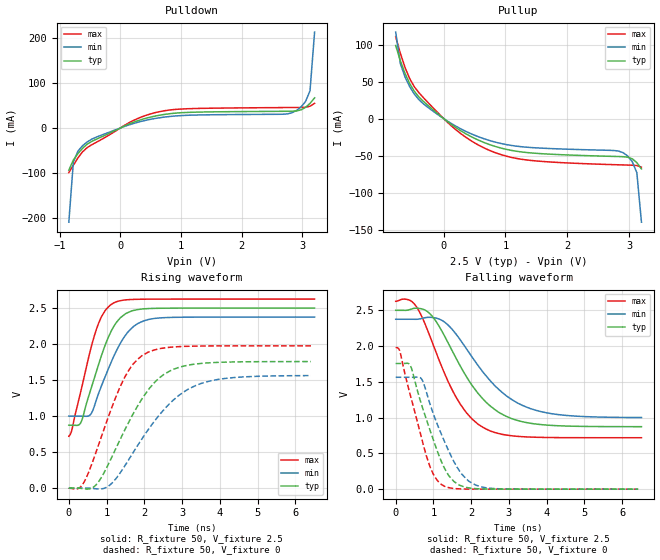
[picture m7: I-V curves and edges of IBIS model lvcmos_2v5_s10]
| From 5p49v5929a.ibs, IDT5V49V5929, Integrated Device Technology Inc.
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[Model]   lvcmos_2v5_s10
Model_type   Output
Polarity   Non-Inverting
|   typ   min   max
C_comp   2pF   1.5pF   2.5pF
Vmeas = 1.25V
Rref = 50
Cref = 0
Vref = 1.25V
|   typ   min   max
[Voltage range]   2.5V   2.375V   2.625V
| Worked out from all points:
|   slope of the pulldown table from 0 to 0.375 V, typ, clamps not added: 18.9 ohm
|   slope of the pullup table from 0 to 0.375 V, typ, clamps not added: 17.6 ohm
|   rising waveform, R_fixture 50, V_fixture 2.5: 20-80 % time 636ps typ, 708ps min, 552ps max; typ from 0.873 V to 2.5 V
|   falling waveform, R_fixture 50, V_fixture 2.5: 20-80 % time 1.17ns typ, 1.32ns min, 1ns max; typ from 2.5 V to 0.873 V
|   rising waveform, R_fixture 50, V_fixture 0: 20-80 % time 1.1ns typ, 1.34ns min, 874ps max; typ from 0 V to 1.76 V
|   falling waveform, R_fixture 50, V_fixture 0: 20-80 % time 679ps typ, 746ps min, 598ps max; typ from 1.76 V to 0 V
[Pulldown]
|Voltage   I (typ)   I (min)   I (max)
|Note, modeling breaks down at 250mA and above.  This is well beyond the functional   |
|operating range of the device.  Should this scenario occur, catastrophic failure and   |
|possible damage to the device and/or board is of higher concern than the I-V curve   |
|behavior.  The IBIS checker will flag currents in excess of 10A with warnings.  Lines   |
|with currents in excess of 0.35 A have been commented out.  The points still remain|
|available to the user if the user desires to use them.   |
|-2.50000e+00   -2.65608e+02   -2.29941e+02   -3.26165e+02
|-2.42500e+00   -2.52343e+02   -2.18875e+02   -3.09252e+02
|-2.35000e+00   -2.39080e+02   -2.07811e+02   -2.92340e+02
|-2.27500e+00   -2.25818e+02   -1.96747e+02   -2.75428e+02
|-2.20000e+00   -2.12557e+02   -1.85685e+02   -2.58518e+02
|-2.12500e+00   -1.99297e+02   -1.74624e+02   -2.41608e+02
|-2.05000e+00   -1.86039e+02   -1.63565e+02   -2.24700e+02
|-1.97500e+00   -1.72782e+02   -1.52508e+02   -2.07793e+02
|-1.90000e+00   -1.59528e+02   -1.41453e+02   -1.90888e+02
|-1.82500e+00   -1.46276e+02   -1.30401e+02   -1.73985e+02
|-1.75000e+00   -1.33027e+02   -1.19352e+02   -1.57085e+02
|-1.67500e+00   -1.19782e+02   -1.08307e+02   -1.40188e+02
|-1.60000e+00   -1.06542e+02   -9.72682e+01   -1.23295e+02
|-1.52500e+00   -9.33090e+01   -8.62359e+01   -1.06409e+02
|-1.45000e+00   -8.00850e+01   -7.52129e+01   -8.95309e+01
|-1.37500e+00   -6.68743e+01   -6.42029e+01   -7.26657e+01
|-1.30000e+00   -5.36897e+01   -5.32178e+01   -5.58258e+01
|-1.22500e+00   -4.05463e+01   -4.22664e+01   -3.90371e+01
|-1.15000e+00   -2.74527e+01   -3.13543e+01   -2.23159e+01
|-1.07500e+00   -1.44175e+01   -2.04874e+01   -5.67477e+00
|-1.00000e+00   -2.41445e+00   -9.65733e+00   -2.99544e-01
|-9.25000e-01   -2.45532e-01   -1.42571e+00   -1.20411e-01
-850mV    -93.99mA   -210mA     -99.45mA
-775mV    -71.55mA   -76.14mA   -83.12mA
-700mV    -57.23mA   -51.66mA   -66.79mA
-550mV    -36.49mA   -31.4mA    -44.03mA
200mV     11.86mA    9.308mA    15.7mA
650mV     28.48mA    22.79mA    36.43mA
1.175V    34.92mA    28.53mA    43.11mA
2.825V    37.25mA    33.68mA    45.54mA
2.975V    40.25mA    46.76mA    45.71mA
3.05V     45.87mA    58.57mA    46.09mA
3.125V    54.76mA    82.96mA    48.46mA
3.2V      67.01mA    213.6mA    54.81mA
| 3.27500e+00   8.22893e-02   1.48202e+00   6.52461e-02
| 3.35000e+00   1.11691e-01   1.21021e+01   7.95740e-02
| 3.42500e+00   4.17187e-01   2.91692e+01   9.49987e-02
| 3.50000e+00   5.44922e+00   4.62676e+01   1.08609e-01
| 3.57500e+00   2.52763e+01   6.34104e+01   1.52479e-01
| 3.65000e+00   4.58138e+01   8.05959e+01   1.32846e+00
| 3.72500e+00   6.64097e+01   9.78129e+01   2.01980e+01
| 3.80000e+00   8.70553e+01   1.15052e+02   4.64595e+01
| 3.87500e+00   1.07734e+02   1.32307e+02   7.28003e+01
| 3.95000e+00   1.28434e+02   1.49572e+02   9.91974e+01
| 4.02500e+00   1.49148e+02   1.66846e+02   1.25626e+02
| 4.10000e+00   1.69871e+02   1.84125e+02   1.52073e+02
| 4.17500e+00   1.90602e+02   2.01410e+02   1.78532e+02
| 4.25000e+00   2.11338e+02   2.18698e+02   2.05000e+02
| 4.32500e+00   2.32079e+02   2.35990e+02   2.31473e+02
| 4.40000e+00   2.52823e+02   2.53284e+02   2.57951e+02
| 4.47500e+00   2.73570e+02   2.70581e+02   2.84433e+02
| 4.55000e+00   2.94320e+02   2.87880e+02   3.10918e+02
| 4.62500e+00   3.15072e+02   3.05181e+02   3.37405e+02
| 4.70000e+00   3.35826e+02   3.22484e+02   3.63895e+02
| 4.77500e+00   3.56582e+02   3.39789e+02   3.90387e+02
| 4.85000e+00   3.77340e+02   3.57095e+02   4.16881e+02
| 4.92500e+00   3.98099e+02   3.74402e+02   4.43377e+02
| 5.00000e+00   4.18860e+02   3.91711e+02   4.69874e+02
[Pullup]
|Voltage   I (typ)   I (min)   I (max)
|Note, modeling breaks down at 250mA and above.  This is well beyond the functional   |
|operating range of the device.  Should this scenario occur, catastrophic failure and   |
|possible damage to the device and/or board is of higher concern than the I-V curve   |
|behavior.  The IBIS checker will flag currents in excess of 10A with warnings.  Lines   |
|with currents in excess of 0.35 A have been commented out.  The points still remain|
|available to the user if the user desires to use them.   |
|-2.50000e+00   4.18924e+02   3.62922e+02   5.14110e+02
|-2.42500e+00   3.98163e+02   3.45615e+02   4.87611e+02
|-2.35000e+00   3.77403e+02   3.28309e+02   4.61112e+02
|-2.27500e+00   3.56644e+02   3.11005e+02   4.34615e+02
|-2.20000e+00   3.35887e+02   2.93702e+02   4.08119e+02
|-2.12500e+00   3.15132e+02   2.76401e+02   3.81625e+02
|-2.05000e+00   2.94379e+02   2.59102e+02   3.55132e+02
|-1.97500e+00   2.73627e+02   2.41805e+02   3.28642e+02
|-1.90000e+00   2.52879e+02   2.24511e+02   3.02154e+02
|-1.82500e+00   2.32133e+02   2.07220e+02   2.75668e+02
|-1.75000e+00   2.11391e+02   1.89933e+02   2.49186e+02
|-1.67500e+00   1.90653e+02   1.72650e+02   2.22708e+02
|-1.60000e+00   1.69920e+02   1.55373e+02   1.96234e+02
|-1.52500e+00   1.49194e+02   1.38102e+02   1.69767e+02
|-1.45000e+00   1.28478e+02   1.20842e+02   1.43309e+02
|-1.37500e+00   1.07776e+02   1.03595e+02   1.16864e+02
|-1.30000e+00   8.70950e+01   8.63670e+01   9.04416e+01
|-1.22500e+00   6.64470e+01   6.91675e+01   6.40570e+01
|-1.15000e+00   4.58485e+01   5.20071e+01   3.77381e+01
|-1.07500e+00   2.53080e+01   3.48921e+01   1.14975e+01
|-1.00000e+00   5.47770e+00   1.78138e+01   5.20511e-01
|-9.25000e-01   4.42241e-01   3.17254e+00   1.56153e-01
|-8.50000e-01   1.32908e-01   3.92497e-01   1.29698e-01
-775mV    98.68mA    116.8mA    110.3mA
-700mV    78.11mA    74.31mA    88.11mA
-625mV    61.11mA    56.31mA    69.18mA
-475mV    36.93mA    33.22mA    43.05mA
-325mV    23.07mA    19.8mA     28.08mA
125mV     -7.951mA   -6.687mA   -9.848mA
575mV     -29.56mA   -24.95mA   -36.3mA
1.325V    -45.7mA    -38.54mA   -55.7mA
2.9V      -51.46mA   -45.91mA   -62.61mA
3.05V     -54.28mA   -57.96mA   -62.98mA
3.125V    -59.49mA   -72.96mA   -63.43mA
3.2V      -67.99mA   -139.9mA   -65.6mA
| 3.27500e+00   -7.95179e-02   -7.11252e-01   -7.19088e-02
| 3.35000e+00   -9.96915e-02   -6.05603e+00   -8.27613e-02
| 3.42500e+00   -2.49209e-01   -1.68766e+01   -9.65190e-02
| 3.50000e+00   -2.41654e+00   -2.77285e+01   -1.10622e-01
| 3.57500e+00   -1.44189e+01   -3.86247e+01   -1.40364e-01
| 3.65000e+00   -2.74535e+01   -4.95634e+01   -6.78328e-01
| 3.72500e+00   -4.05466e+01   -6.05360e+01   -1.12141e+01
| 3.80000e+00   -5.36896e+01   -7.15395e+01   -2.78806e+01
| 3.87500e+00   -6.68736e+01   -8.25581e+01   -4.46279e+01
| 3.95000e+00   -8.00835e+01   -9.35871e+01   -6.14343e+01
| 4.02500e+00   -9.33072e+01   -1.04624e+02   -7.82862e+01
| 4.10000e+00   -1.06540e+02   -1.15666e+02   -9.51560e+01
| 4.17500e+00   -1.19780e+02   -1.26714e+02   -1.12037e+02
| 4.25000e+00   -1.33024e+02   -1.37764e+02   -1.28926e+02
| 4.32500e+00   -1.46273e+02   -1.48818e+02   -1.45820e+02
| 4.40000e+00   -1.59525e+02   -1.59874e+02   -1.62718e+02
| 4.47500e+00   -1.72779e+02   -1.70933e+02   -1.79619e+02
| 4.55000e+00   -1.86036e+02   -1.81993e+02   -1.96523e+02
| 4.62500e+00   -1.99294e+02   -1.93055e+02   -2.13429e+02
| 4.70000e+00   -2.12554e+02   -2.04118e+02   -2.30337e+02
| 4.77500e+00   -2.25816e+02   -2.15182e+02   -2.47246e+02
| 4.85000e+00   -2.39078e+02   -2.26248e+02   -2.64156e+02
| 4.92500e+00   -2.52342e+02   -2.37314e+02   -2.81068e+02
| 5.00000e+00   -2.65606e+02   -2.48382e+02   -2.97980e+02
[Ramp]
|   typ   min   max
dV/dt_r   1.062/1.108n   0.945/1.348n   1.194/0.879n
dV/dt_f   0.993/1.179n   0.84/1.332n   1.162/1.013n
R_load =   50
[Rising Waveform]
R_fixture = 50
V_fixture = 2.5   |Vcc_typ
V_fixture_min = 2.375 |Vcc_min
V_fixture_max = 2.625 |Vcc_max
C_fixture = 0.0p
| Time   typ   min   max
| 0.00000e+00   8.73021e-01   9.99328e-01   7.18803e-01
| 2.82958e-12   8.73021e-01   9.99328e-01   7.18803e-01
| 5.01945e-12   8.73021e-01   9.99328e-01   7.18803e-01
| 5.29250e-12   8.73021e-01   9.99328e-01   7.18803e-01
| 8.83938e-12   8.73021e-01   9.99328e-01   7.18803e-01
| 1.58159e-11   8.73021e-01   9.99328e-01   7.18803e-01
| 1.65816e-11   8.73021e-01   9.99328e-01   7.18803e-01
| 3.09307e-11   8.73021e-01   9.99328e-01   7.18803e-01
| 4.33456e-11   8.73021e-01   9.99328e-01   7.18803e-01
| 4.84997e-11   8.73021e-01   9.99328e-01   7.18803e-01
| 5.92498e-11   8.73021e-01   9.99328e-01   7.18803e-01
| 6.33903e-11   8.73021e-01   9.99328e-01   7.18803e-01
| 7.24942e-11   8.73021e-01   9.99328e-01   7.18803e-01
| 7.37142e-11   8.73021e-01   9.99328e-01   7.18803e-01
| 7.72112e-11   8.73021e-01   9.99328e-01   7.18803e-01
| 8.08094e-11   8.73021e-01   9.99328e-01   7.18803e-01
| 8.33740e-11   8.73021e-01   9.99328e-01   7.18803e-01
| 8.93880e-11   8.73021e-01   9.99328e-01   7.18803e-01
| 1.00166e-10   8.73021e-01   9.99328e-01   7.18804e-01
| 1.04900e-10   8.73021e-01   9.99328e-01   7.18804e-01
| 1.14234e-10   8.73022e-01   9.99329e-01   7.18804e-01
| 1.18465e-10   8.73022e-01   9.99329e-01   7.18804e-01
| 1.25023e-10   8.73022e-01   9.99329e-01   7.18804e-01
| 1.37358e-10   8.73022e-01   9.99329e-01   7.18804e-01
| 1.40589e-10   8.73022e-01   9.99329e-01   7.18804e-01
| 1.51767e-10   8.73021e-01   9.99329e-01   7.18802e-01
| 1.61060e-10   8.73019e-01   9.99327e-01   7.18800e-01
| 1.69091e-10   8.73016e-01   9.99324e-01   7.18797e-01
| 1.80923e-10   8.73011e-01   9.99320e-01   7.18792e-01
| 1.98540e-10   8.73004e-01   9.99312e-01   7.18784e-01
| 2.03752e-10   8.73002e-01   9.99309e-01   7.18782e-01
| 2.22970e-10   8.72994e-01   9.99302e-01   7.18775e-01
| 2.39229e-10   8.72989e-01   9.99297e-01   7.18772e-01
| 2.45359e-10   8.72988e-01   9.99296e-01   7.18773e-01
| 2.53236e-10   8.72988e-01   9.99294e-01   7.18776e-01
| 2.61834e-10   8.72990e-01   9.99294e-01   7.18782e-01
| 2.68845e-10   8.72993e-01   9.99294e-01   7.18785e-01
| 2.75098e-10   8.72996e-01   9.99296e-01   7.18788e-01
| 2.84408e-10   8.73000e-01   9.99300e-01   7.18791e-01
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0s        873mV      999.3mV    718.8mV
80.48ps   872.2mV    998.7mV    807.1mV
308.1ps   900.3mV    998.4mV    1.322V
585.2ps   1.376V     1.029V     1.942V
865.1ps   1.841V     1.42V      2.381V
1.196ns   2.249V     1.835V     2.574V
1.366ns   2.366V     2.012V     2.603V
1.631ns   2.452V     2.204V     2.618V
2.106ns   2.493V     2.341V     2.624V
6.509ns   2.5V       2.375V     2.625V
[Falling Waveform]
R_fixture = 50
V_fixture = 2.5   |Vcc_typ
V_fixture_min = 2.375 |Vcc_min
V_fixture_max = 2.625 |Vcc_max
C_fixture = 0.0p
| Time   typ   min   max
| 0.00000e+00   2.50000e+00   2.37500e+00   2.62500e+00
| 2.82958e-12   2.50000e+00   2.37500e+00   2.62500e+00
| 5.01945e-12   2.50000e+00   2.37500e+00   2.62500e+00
| 5.29250e-12   2.50000e+00   2.37500e+00   2.62500e+00
| 8.83938e-12   2.50000e+00   2.37500e+00   2.62500e+00
| 1.58159e-11   2.50000e+00   2.37500e+00   2.62500e+00
| 1.65816e-11   2.50000e+00   2.37500e+00   2.62500e+00
| 3.09306e-11   2.50000e+00   2.37500e+00   2.62500e+00
| 4.33456e-11   2.50000e+00   2.37500e+00   2.62500e+00
| 4.84997e-11   2.50000e+00   2.37500e+00   2.62500e+00
| 5.92499e-11   2.50000e+00   2.37500e+00   2.62500e+00
| 6.33904e-11   2.50000e+00   2.37500e+00   2.62500e+00
| 7.24942e-11   2.50000e+00   2.37500e+00   2.62500e+00
| 7.37143e-11   2.50000e+00   2.37500e+00   2.62500e+00
| 7.72112e-11   2.50000e+00   2.37500e+00   2.62500e+00
| 8.08094e-11   2.50000e+00   2.37500e+00   2.62500e+00
| 8.33740e-11   2.50000e+00   2.37500e+00   2.62500e+00
| 8.93881e-11   2.50000e+00   2.37500e+00   2.62500e+00
| 1.00162e-10   2.50000e+00   2.37500e+00   2.62500e+00
| 1.04901e-10   2.50000e+00   2.37500e+00   2.62500e+00
| 1.14235e-10   2.50000e+00   2.37500e+00   2.62500e+00
| 1.18460e-10   2.50000e+00   2.37500e+00   2.62500e+00
| 1.25023e-10   2.50000e+00   2.37500e+00   2.62500e+00
| 1.37358e-10   2.50000e+00   2.37500e+00   2.62500e+00
| 1.40585e-10   2.50000e+00   2.37500e+00   2.62500e+00
| 1.51766e-10   2.50000e+00   2.37500e+00   2.62500e+00
| 1.61057e-10   2.50000e+00   2.37500e+00   2.62500e+00
| 1.69080e-10   2.50000e+00   2.37500e+00   2.62500e+00
| 1.80919e-10   2.49999e+00   2.37500e+00   2.62499e+00
| 1.99499e-10   2.49999e+00   2.37499e+00   2.62499e+00
| 2.05003e-10   2.49999e+00   2.37499e+00   2.62499e+00
| 2.24273e-10   2.49998e+00   2.37498e+00   2.62498e+00
| 2.39981e-10   2.49998e+00   2.37498e+00   2.62498e+00
| 2.47899e-10   2.49998e+00   2.37498e+00   2.62498e+00
| 2.62665e-10   2.49998e+00   2.37498e+00   2.62499e+00
| 2.73527e-10   2.49998e+00   2.37498e+00   2.62499e+00
| 2.79768e-10   2.49998e+00   2.37498e+00   2.62499e+00
| 2.89155e-10   2.49999e+00   2.37498e+00   2.62500e+00
| 2.95491e-10   2.49999e+00   2.37498e+00   2.62500e+00
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0s        2.5V       2.375V     2.625V
478.7ps   2.527V     2.375V     2.597V
923ps     2.444V     2.401V     2.115V
1.275ns   2.159V     2.343V     1.642V
1.606ns   1.824V     2.163V     1.28V
1.998ns   1.47V      1.865V     994.9mV
2.318ns   1.257V     1.632V     861.7mV
2.924ns   1.019V     1.307V     756.9mV
3.686ns   911.9mV    1.107V     726mV
6.509ns   873.4mV    1.001V     718.8mV
[Rising Waveform]
R_fixture = 50
V_fixture = 0
C_fixture = 0.0p
| Time   typ   min   max
| 0.00000e+00   6.87937e-09   4.94005e-08   5.62352e-09
| 2.82958e-12   9.38656e-09   5.18161e-08   8.19508e-09
| 5.01945e-12   1.05516e-08   5.29861e-08   9.33315e-09
| 5.29250e-12   1.06562e-08   5.30562e-08   9.47156e-09
| 8.83938e-12   1.14741e-08   5.38988e-08   1.01694e-08
| 1.58159e-11   9.80859e-09   5.35126e-08   7.82907e-09
| 1.65816e-11   9.85399e-09   5.39566e-08   7.55918e-09
| 3.09307e-11   1.50805e-08   6.38774e-08   9.11730e-09
| 4.33456e-11   5.21227e-08   9.86830e-08   4.07091e-08
| 4.84997e-11   6.75010e-08   1.14222e-07   5.79266e-08
| 5.92498e-11   1.01050e-07   1.49539e-07   9.24295e-08
| 6.33903e-11   1.01613e-07   1.48222e-07   1.03899e-07
| 7.24942e-11   7.31413e-08   1.02772e-07   9.86080e-08
| 7.37142e-11   5.87738e-08   7.73613e-08   9.03171e-08
| 7.72112e-11   -3.94951e-09   4.52995e-09   5.74755e-08
| 8.08094e-11   -7.54237e-08   -9.71747e-08   1.81975e-08
| 8.33740e-11   -1.30062e-07   -1.50154e-07   1.62220e-08
| 8.93880e-11   -1.48519e-07   -2.64374e-07   4.53045e-08
| 1.00166e-10   1.24254e-07   -4.29323e-08   3.33852e-07
| 1.04900e-10   3.01602e-07   1.48683e-07   5.72718e-07
| 1.14234e-10   9.37278e-07   7.74393e-07   9.81604e-07
| 1.18465e-10   1.16633e-06   1.08464e-06   1.13897e-06
| 1.25023e-10   1.50552e-06   1.56545e-06   1.16097e-06
| 1.37358e-10   1.64317e-06   1.93794e-06   9.99908e-07
| 1.40589e-10   1.48293e-06   1.94633e-06   9.03754e-07
| 1.51767e-10   5.03721e-07   1.34352e-06   -1.49195e-07
| 1.61060e-10   -1.03002e-06   -4.00874e-07   -2.42878e-06
| 1.69091e-10   -3.75459e-06   -2.59222e-06   -4.51622e-06
| 1.80923e-10   -7.88012e-06   -6.70546e-06   -9.20462e-06
| 1.98540e-10   -1.48331e-05   -1.37393e-05   -1.59118e-05
| 2.03752e-10   -1.65288e-05   -1.57793e-05   -1.78548e-05
| 2.22970e-10   -2.24873e-05   -2.19399e-05   -2.34613e-05
| 2.39229e-10   -2.68323e-05   -2.61765e-05   -2.48219e-05
| 2.45359e-10   -2.73690e-05   -2.77433e-05   -2.41161e-05
| 2.53236e-10   -2.75121e-05   -2.88971e-05   -2.07569e-05
| 2.61834e-10   -2.50538e-05   -2.91232e-05   -1.51028e-05
| 2.68845e-10   -2.15946e-05   -2.81639e-05   -1.16643e-05
| 2.75098e-10   -1.87424e-05   -2.59563e-05   -8.96290e-06
| 2.84409e-10   -1.48308e-05   -2.25961e-05   -6.64248e-06
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0s        6.879nV    49.4nV     5.624nV
349.5ps   -5.964mV   81.91uV    38.42mV
744.3ps   58.17mV    -11.4mV    533.7mV
1.077ns   362.8mV    37.42mV    1.033V
1.444ns   765.9mV    276.5mV    1.5V
1.932ns   1.234V     679mV      1.837V
2.572ns   1.595V     1.12V      1.95V
3.498ns   1.731V     1.452V     1.973V
4.458ns   1.752V     1.538V     1.975V
6.413ns   1.757V     1.562V     1.975V
[Falling Waveform]
R_fixture = 50
V_fixture = 0
C_fixture = 0.0p
| Time   typ   min   max
| 0.00000e+00   1.75700e+00   1.56389e+00   1.97545e+00
| 1.87623e-10   1.75699e+00   1.56388e+00   1.97544e+00
| 2.18725e-10   1.75698e+00   1.56387e+00   1.97543e+00
| 2.63808e-10   1.75697e+00   1.56386e+00   1.97543e+00
| 3.01812e-10   1.75699e+00   1.56387e+00   1.97544e+00
| 3.86470e-10   1.75699e+00   1.56388e+00   1.97545e+00
| 4.31207e-10   1.75700e+00   1.56389e+00   1.97545e+00
| 7.14375e-10   1.75700e+00   1.56390e+00   1.97546e+00
| 7.53456e-10   1.75700e+00   1.56389e+00   1.97545e+00
| 8.44629e-10   1.75700e+00   1.56390e+00   1.97544e+00
| 9.20641e-10   1.75699e+00   1.56390e+00   1.97545e+00
| 9.89803e-10   1.75699e+00   1.56389e+00   1.97546e+00
| 1.05820e-09   1.75699e+00   1.56389e+00   1.97546e+00
| 1.12623e-09   1.75701e+00   1.56389e+00   1.97545e+00
| 1.23239e-09   1.75701e+00   1.56389e+00   1.97547e+00
| 1.33822e-09   1.75701e+00   1.56391e+00   1.97546e+00
| 1.39891e-09   1.75701e+00   1.56391e+00   1.97541e+00
| 1.42492e-09   1.75702e+00   1.56391e+00   1.97551e+00
| 1.43750e-09   1.75702e+00   1.56391e+00   1.97561e+00
| 1.45507e-09   1.75702e+00   1.56390e+00   1.97588e+00
| 1.46542e-09   1.75703e+00   1.56390e+00   1.97617e+00
| 1.47364e-09   1.75703e+00   1.56390e+00   1.97650e+00
| 1.49003e-09   1.75703e+00   1.56390e+00   1.97748e+00
| 1.50584e-09   1.75703e+00   1.56390e+00   1.97832e+00
| 1.51626e-09   1.75703e+00   1.56390e+00   1.97838e+00
| 1.52671e-09   1.75703e+00   1.56391e+00   1.97796e+00
| 1.54564e-09   1.75703e+00   1.56391e+00   1.97464e+00
| 1.55852e-09   1.75703e+00   1.56391e+00   1.96945e+00
| 1.57739e-09   1.75702e+00   1.56391e+00   1.95621e+00
| 1.59185e-09   1.75701e+00   1.56391e+00   1.93967e+00
| 1.60702e-09   1.75699e+00   1.56391e+00   1.91503e+00
| 1.62557e-09   1.75698e+00   1.56392e+00   1.87671e+00
| 1.64110e-09   1.75697e+00   1.56392e+00   1.84050e+00
| 1.65721e-09   1.75698e+00   1.56392e+00   1.80133e+00
| 1.67702e-09   1.75704e+00   1.56393e+00   1.75189e+00
| 1.69225e-09   1.75712e+00   1.56393e+00   1.71388e+00
| 1.70423e-09   1.75723e+00   1.56393e+00   1.68504e+00
| 1.71971e-09   1.75747e+00   1.56393e+00   1.64846e+00
| 1.73061e-09   1.75770e+00   1.56393e+00   1.62340e+00
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0s        1.757V     1.564V     1.975V
116.2ps   1.757V     1.564V     1.915V
381.5ps   1.735V     1.564V     1.326V
684.5ps   1.182V     1.541V     716.1mV
922.6ps   803.9mV    1.168V     294.9mV
1.215ns   379.5mV    761.2mV    63.28mV
1.401ns   192.4mV    539.1mV    22.13mV
1.754ns   42.69mV    208.4mV    3.13mV
2.227ns   4.561mV    38.09mV    373.8uV
6.421ns   -3.447uV   -1.481uV   -2.667uV
